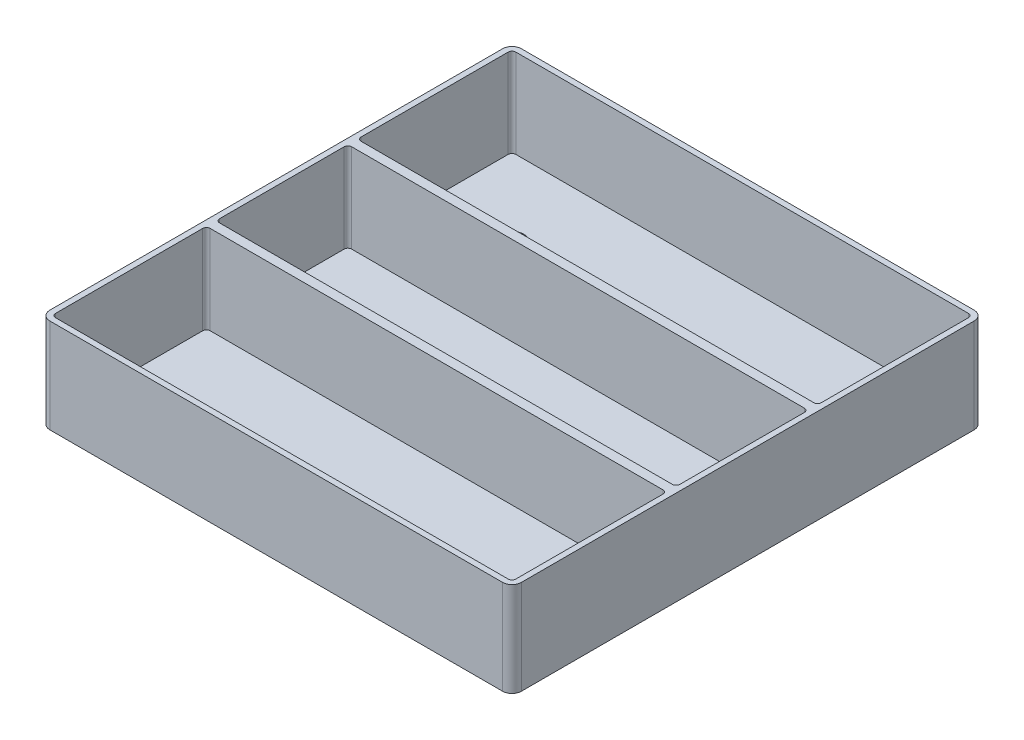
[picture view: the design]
ISO-10303-21;
HEADER;
FILE_DESCRIPTION(('STEP AP214'),'2;1');
FILE_NAME('part.step','',(''),(''),'','','');
FILE_SCHEMA(('AUTOMOTIVE_DESIGN { 1 0 10303 214 1 1 1 1 }'));
ENDSEC;
DATA;
#1=APPLICATION_CONTEXT('core data for automotive mechanical design processes');
#2=APPLICATION_PROTOCOL_DEFINITION('international standard','automotive_design',2000,#1);
#3=PRODUCT_CONTEXT('',#1,'mechanical');
#4=PRODUCT('Part','Part','',(#3));
#5=PRODUCT_RELATED_PRODUCT_CATEGORY('part','',(#4));
#6=PRODUCT_DEFINITION_FORMATION('','',#4);
#7=PRODUCT_DEFINITION_CONTEXT('part definition',#1,'design');
#8=PRODUCT_DEFINITION('design','',#6,#7);
#9=PRODUCT_DEFINITION_SHAPE('','',#8);
#10=(LENGTH_UNIT() NAMED_UNIT(*) SI_UNIT(.MILLI.,.METRE.));
#11=(NAMED_UNIT(*) PLANE_ANGLE_UNIT() SI_UNIT($,.RADIAN.));
#12=(NAMED_UNIT(*) SI_UNIT($,.STERADIAN.) SOLID_ANGLE_UNIT());
#13=UNCERTAINTY_MEASURE_WITH_UNIT(LENGTH_MEASURE(1.E-05),#10,'distance_accuracy_value','');
#14=(GEOMETRIC_REPRESENTATION_CONTEXT(3) GLOBAL_UNCERTAINTY_ASSIGNED_CONTEXT((#13)) GLOBAL_UNIT_ASSIGNED_CONTEXT((#10,
#11,#12)) REPRESENTATION_CONTEXT('',''));
#15=CARTESIAN_POINT('',(0.,0.,0.));
#16=DIRECTION('',(0.,0.,1.));
#17=DIRECTION('',(1.,0.,0.));
#18=AXIS2_PLACEMENT_3D('',#15,#16,#17);
#19=CARTESIAN_POINT('',(-61.976,25.4,-63.5));
#20=DIRECTION('',(1.,0.,0.));
#21=DIRECTION('',(0.,0.,-1.));
#22=AXIS2_PLACEMENT_3D('',#19,#20,#21);
#23=PLANE('',#22);
#24=DIRECTION('',(0.,0.,1.));
#25=VECTOR('',#24,1.);
#26=CARTESIAN_POINT('',(-61.976,1.524,-63.5));
#27=LINE('',#26,#25);
#28=CARTESIAN_POINT('',(-61.976,1.524,-16.764));
#29=VERTEX_POINT('',#28);
#30=CARTESIAN_POINT('',(-61.976,1.524,16.764));
#31=VERTEX_POINT('',#30);
#32=EDGE_CURVE('E515',#29,#31,#27,.T.);
#33=ORIENTED_EDGE('',*,*,#32,.F.);
#34=DIRECTION('',(0.,-1.,0.));
#35=VECTOR('',#34,1.);
#36=CARTESIAN_POINT('',(-61.976,25.4,-16.764));
#37=LINE('',#36,#35);
#38=CARTESIAN_POINT('',(-61.976,25.4,-16.764));
#39=VERTEX_POINT('',#38);
#40=EDGE_CURVE('E397',#29,#39,#37,.F.);
#41=ORIENTED_EDGE('',*,*,#40,.T.);
#42=DIRECTION('',(0.,0.,1.));
#43=VECTOR('',#42,1.);
#44=CARTESIAN_POINT('',(-61.976,25.4,-63.5));
#45=LINE('',#44,#43);
#46=CARTESIAN_POINT('',(-61.976,25.4,16.764));
#47=VERTEX_POINT('',#46);
#48=EDGE_CURVE('E288',#39,#47,#45,.T.);
#49=ORIENTED_EDGE('',*,*,#48,.T.);
#50=DIRECTION('',(0.,-1.,0.));
#51=VECTOR('',#50,1.);
#52=CARTESIAN_POINT('',(-61.976,25.4,16.764));
#53=LINE('',#52,#51);
#54=EDGE_CURVE('E394',#47,#31,#53,.T.);
#55=ORIENTED_EDGE('',*,*,#54,.T.);
#56=EDGE_LOOP('',(#33,#41,#49,#55));
#57=FACE_BOUND('',#56,.T.);
#58=ADVANCED_FACE('F41',(#57),#23,.T.);
#59=CARTESIAN_POINT('',(61.976,25.4,-63.5));
#60=DIRECTION('',(-1.,0.,0.));
#61=DIRECTION('',(0.,0.,1.));
#62=AXIS2_PLACEMENT_3D('',#59,#60,#61);
#63=PLANE('',#62);
#64=DIRECTION('',(0.,0.,-1.));
#65=VECTOR('',#64,1.);
#66=CARTESIAN_POINT('',(61.976,1.524,-63.5));
#67=LINE('',#66,#65);
#68=CARTESIAN_POINT('',(61.976,1.524,16.764));
#69=VERTEX_POINT('',#68);
#70=CARTESIAN_POINT('',(61.976,1.524,-16.764));
#71=VERTEX_POINT('',#70);
#72=EDGE_CURVE('E458',#69,#71,#67,.T.);
#73=ORIENTED_EDGE('',*,*,#72,.F.);
#74=DIRECTION('',(0.,-1.,0.));
#75=VECTOR('',#74,1.);
#76=CARTESIAN_POINT('',(61.976,25.4,16.764));
#77=LINE('',#76,#75);
#78=CARTESIAN_POINT('',(61.976,25.4,16.764));
#79=VERTEX_POINT('',#78);
#80=EDGE_CURVE('E421',#69,#79,#77,.F.);
#81=ORIENTED_EDGE('',*,*,#80,.T.);
#82=DIRECTION('',(0.,0.,-1.));
#83=VECTOR('',#82,1.);
#84=CARTESIAN_POINT('',(61.976,25.4,-63.5));
#85=LINE('',#84,#83);
#86=CARTESIAN_POINT('',(61.976,25.4,-16.764));
#87=VERTEX_POINT('',#86);
#88=EDGE_CURVE('E299',#79,#87,#85,.T.);
#89=ORIENTED_EDGE('',*,*,#88,.T.);
#90=DIRECTION('',(0.,-1.,0.));
#91=VECTOR('',#90,1.);
#92=CARTESIAN_POINT('',(61.976,25.4,-16.764));
#93=LINE('',#92,#91);
#94=EDGE_CURVE('E418',#87,#71,#93,.T.);
#95=ORIENTED_EDGE('',*,*,#94,.T.);
#96=EDGE_LOOP('',(#73,#81,#89,#95));
#97=FACE_BOUND('',#96,.T.);
#98=ADVANCED_FACE('F585',(#97),#63,.T.);
#99=CARTESIAN_POINT('',(-63.5,1.524,63.5));
#100=DIRECTION('',(0.,1.,0.));
#101=DIRECTION('',(0.,0.,1.));
#102=AXIS2_PLACEMENT_3D('',#99,#100,#101);
#103=PLANE('',#102);
#104=DIRECTION('',(-1.,0.,0.));
#105=VECTOR('',#104,1.);
#106=CARTESIAN_POINT('',(-63.5,1.524,-17.78));
#107=LINE('',#106,#105);
#108=CARTESIAN_POINT('',(60.96,1.524,-17.78));
#109=VERTEX_POINT('',#108);
#110=CARTESIAN_POINT('',(-60.96,1.524,-17.78));
#111=VERTEX_POINT('',#110);
#112=EDGE_CURVE('E362',#109,#111,#107,.T.);
#113=ORIENTED_EDGE('',*,*,#112,.T.);
#114=CARTESIAN_POINT('',(-60.96,1.524,-16.764));
#115=DIRECTION('',(0.,1.,0.));
#116=DIRECTION('',(0.,0.,1.));
#117=AXIS2_PLACEMENT_3D('',#114,#115,#116);
#118=CIRCLE('',#117,1.016);
#119=EDGE_CURVE('E392',#111,#29,#118,.T.);
#120=ORIENTED_EDGE('',*,*,#119,.T.);
#121=ORIENTED_EDGE('',*,*,#32,.T.);
#122=CARTESIAN_POINT('',(-60.96,1.524,16.764));
#123=DIRECTION('',(0.,1.,0.));
#124=DIRECTION('',(0.,0.,1.));
#125=AXIS2_PLACEMENT_3D('',#122,#123,#124);
#126=CIRCLE('',#125,1.016);
#127=CARTESIAN_POINT('',(-60.96,1.524,17.78));
#128=VERTEX_POINT('',#127);
#129=EDGE_CURVE('E390',#31,#128,#126,.T.);
#130=ORIENTED_EDGE('',*,*,#129,.T.);
#131=DIRECTION('',(1.,0.,0.));
#132=VECTOR('',#131,1.);
#133=CARTESIAN_POINT('',(-63.5,1.524,17.78));
#134=LINE('',#133,#132);
#135=CARTESIAN_POINT('',(60.96,1.524,17.78));
#136=VERTEX_POINT('',#135);
#137=EDGE_CURVE('E495',#128,#136,#134,.T.);
#138=ORIENTED_EDGE('',*,*,#137,.T.);
#139=CARTESIAN_POINT('',(60.96,1.524,16.764));
#140=DIRECTION('',(0.,1.,0.));
#141=DIRECTION('',(0.,0.,1.));
#142=AXIS2_PLACEMENT_3D('',#139,#140,#141);
#143=CIRCLE('',#142,1.016);
#144=EDGE_CURVE('E388',#136,#69,#143,.T.);
#145=ORIENTED_EDGE('',*,*,#144,.T.);
#146=ORIENTED_EDGE('',*,*,#72,.T.);
#147=CARTESIAN_POINT('',(60.96,1.524,-16.764));
#148=DIRECTION('',(0.,1.,0.));
#149=DIRECTION('',(0.,0.,1.));
#150=AXIS2_PLACEMENT_3D('',#147,#148,#149);
#151=CIRCLE('',#150,1.016);
#152=EDGE_CURVE('E386',#71,#109,#151,.T.);
#153=ORIENTED_EDGE('',*,*,#152,.T.);
#154=EDGE_LOOP('',(#113,#120,#121,#130,#138,#145,#146,#153));
#155=FACE_BOUND('',#154,.T.);
#156=ADVANCED_FACE('F593',(#155),#103,.T.);
#157=CARTESIAN_POINT('',(-61.976,1.524,21.336));
#158=VERTEX_POINT('',#157);
#159=CARTESIAN_POINT('',(-61.976,1.524,60.96));
#160=VERTEX_POINT('',#159);
#161=EDGE_CURVE('E449',#158,#160,#27,.T.);
#162=ORIENTED_EDGE('',*,*,#161,.F.);
#163=DIRECTION('',(0.,-1.,0.));
#164=VECTOR('',#163,1.);
#165=CARTESIAN_POINT('',(-61.976,25.4,21.336));
#166=LINE('',#165,#164);
#167=CARTESIAN_POINT('',(-61.976,25.4,21.336));
#168=VERTEX_POINT('',#167);
#169=EDGE_CURVE('E413',#158,#168,#166,.F.);
#170=ORIENTED_EDGE('',*,*,#169,.T.);
#171=CARTESIAN_POINT('',(-61.976,25.4,60.96));
#172=VERTEX_POINT('',#171);
#173=EDGE_CURVE('E271',#168,#172,#45,.T.);
#174=ORIENTED_EDGE('',*,*,#173,.T.);
#175=DIRECTION('',(0.,1.,0.));
#176=VECTOR('',#175,1.);
#177=CARTESIAN_POINT('',(-61.976,25.4,60.96));
#178=LINE('',#177,#176);
#179=EDGE_CURVE('E512',#160,#172,#178,.T.);
#180=ORIENTED_EDGE('',*,*,#179,.F.);
#181=EDGE_LOOP('',(#162,#170,#174,#180));
#182=FACE_BOUND('',#181,.T.);
#183=ADVANCED_FACE('F588',(#182),#23,.T.);
#184=CARTESIAN_POINT('',(61.976,25.4,60.96));
#185=VERTEX_POINT('',#184);
#186=CARTESIAN_POINT('',(61.976,25.4,21.336));
#187=VERTEX_POINT('',#186);
#188=EDGE_CURVE('E295',#185,#187,#85,.T.);
#189=ORIENTED_EDGE('',*,*,#188,.T.);
#190=DIRECTION('',(0.,-1.,0.));
#191=VECTOR('',#190,1.);
#192=CARTESIAN_POINT('',(61.976,1.524,21.336));
#193=LINE('',#192,#191);
#194=CARTESIAN_POINT('',(61.976,1.524,21.336));
#195=VERTEX_POINT('',#194);
#196=EDGE_CURVE('E415',#187,#195,#193,.T.);
#197=ORIENTED_EDGE('',*,*,#196,.T.);
#198=CARTESIAN_POINT('',(61.976,1.524,60.96));
#199=VERTEX_POINT('',#198);
#200=EDGE_CURVE('E272',#199,#195,#67,.T.);
#201=ORIENTED_EDGE('',*,*,#200,.F.);
#202=DIRECTION('',(0.,1.,0.));
#203=VECTOR('',#202,1.);
#204=CARTESIAN_POINT('',(61.976,25.4,60.96));
#205=LINE('',#204,#203);
#206=EDGE_CURVE('E478',#185,#199,#205,.F.);
#207=ORIENTED_EDGE('',*,*,#206,.F.);
#208=EDGE_LOOP('',(#189,#197,#201,#207));
#209=FACE_BOUND('',#208,.T.);
#210=ADVANCED_FACE('F477',(#209),#63,.T.);
#211=CARTESIAN_POINT('',(-41.275,1.524,41.275));
#212=DIRECTION('',(0.,1.,0.));
#213=DIRECTION('',(0.,0.,1.));
#214=AXIS2_PLACEMENT_3D('',#211,#212,#213);
#215=CIRCLE('',#214,3.175);
#216=CARTESIAN_POINT('',(-41.275,1.524,44.45));
#217=VERTEX_POINT('',#216);
#218=EDGE_CURVE('E1044',#217,#217,#215,.T.);
#219=ORIENTED_EDGE('',*,*,#218,.F.);
#220=EDGE_LOOP('',(#219));
#221=FACE_BOUND('',#220,.T.);
#222=CARTESIAN_POINT('',(44.45,1.524,41.275));
#223=DIRECTION('',(0.,1.,0.));
#224=DIRECTION('',(0.,0.,1.));
#225=AXIS2_PLACEMENT_3D('',#222,#223,#224);
#226=CIRCLE('',#225,3.175);
#227=CARTESIAN_POINT('',(44.45,1.524,44.45));
#228=VERTEX_POINT('',#227);
#229=EDGE_CURVE('E1047',#228,#228,#226,.T.);
#230=ORIENTED_EDGE('',*,*,#229,.F.);
#231=EDGE_LOOP('',(#230));
#232=FACE_BOUND('',#231,.T.);
#233=DIRECTION('',(1.,0.,0.));
#234=VECTOR('',#233,1.);
#235=CARTESIAN_POINT('',(-63.5,1.524,20.32));
#236=LINE('',#235,#234);
#237=CARTESIAN_POINT('',(-60.96,1.524,20.32));
#238=VERTEX_POINT('',#237);
#239=CARTESIAN_POINT('',(60.96,1.524,20.32));
#240=VERTEX_POINT('',#239);
#241=EDGE_CURVE('E491',#238,#240,#236,.T.);
#242=ORIENTED_EDGE('',*,*,#241,.F.);
#243=CARTESIAN_POINT('',(-60.96,1.524,21.336));
#244=DIRECTION('',(0.,1.,0.));
#245=DIRECTION('',(0.,0.,1.));
#246=AXIS2_PLACEMENT_3D('',#243,#244,#245);
#247=CIRCLE('',#246,1.016);
#248=EDGE_CURVE('E411',#238,#158,#247,.T.);
#249=ORIENTED_EDGE('',*,*,#248,.T.);
#250=ORIENTED_EDGE('',*,*,#161,.T.);
#251=CARTESIAN_POINT('',(-60.96,1.524,60.96));
#252=DIRECTION('',(0.,1.,0.));
#253=DIRECTION('',(0.,0.,1.));
#254=AXIS2_PLACEMENT_3D('',#251,#252,#253);
#255=CIRCLE('',#254,1.016);
#256=CARTESIAN_POINT('',(-60.96,1.524,61.976));
#257=VERTEX_POINT('',#256);
#258=EDGE_CURVE('E511',#257,#160,#255,.F.);
#259=ORIENTED_EDGE('',*,*,#258,.F.);
#260=DIRECTION('',(1.,0.,0.));
#261=VECTOR('',#260,1.);
#262=CARTESIAN_POINT('',(-63.5,1.524,61.976));
#263=LINE('',#262,#261);
#264=CARTESIAN_POINT('',(60.96,1.524,61.976));
#265=VERTEX_POINT('',#264);
#266=EDGE_CURVE('E459',#257,#265,#263,.T.);
#267=ORIENTED_EDGE('',*,*,#266,.T.);
#268=CARTESIAN_POINT('',(60.96,1.524,60.96));
#269=DIRECTION('',(0.,1.,0.));
#270=DIRECTION('',(0.,0.,1.));
#271=AXIS2_PLACEMENT_3D('',#268,#269,#270);
#272=CIRCLE('',#271,1.016);
#273=EDGE_CURVE('E473',#199,#265,#272,.F.);
#274=ORIENTED_EDGE('',*,*,#273,.F.);
#275=ORIENTED_EDGE('',*,*,#200,.T.);
#276=CARTESIAN_POINT('',(60.96,1.524,21.336));
#277=DIRECTION('',(0.,1.,0.));
#278=DIRECTION('',(0.,0.,1.));
#279=AXIS2_PLACEMENT_3D('',#276,#277,#278);
#280=CIRCLE('',#279,1.016);
#281=EDGE_CURVE('E409',#195,#240,#280,.T.);
#282=ORIENTED_EDGE('',*,*,#281,.T.);
#283=EDGE_LOOP('',(#242,#249,#250,#259,#267,#274,#275,#282));
#284=FACE_BOUND('',#283,.T.);
#285=ADVANCED_FACE('F471',(#221,#232,#284),#103,.T.);
#286=CARTESIAN_POINT('',(-63.5,25.4,-63.5));
#287=DIRECTION('',(1.,0.,0.));
#288=DIRECTION('',(0.,0.,-1.));
#289=AXIS2_PLACEMENT_3D('',#286,#287,#288);
#290=PLANE('',#289);
#291=DIRECTION('',(0.,-1.,0.));
#292=VECTOR('',#291,1.);
#293=CARTESIAN_POINT('',(-63.5,25.4,60.96));
#294=LINE('',#293,#292);
#295=CARTESIAN_POINT('',(-63.5,0.,60.96));
#296=VERTEX_POINT('',#295);
#297=CARTESIAN_POINT('',(-63.5,25.4,60.96));
#298=VERTEX_POINT('',#297);
#299=EDGE_CURVE('E322',#296,#298,#294,.F.);
#300=ORIENTED_EDGE('',*,*,#299,.T.);
#301=DIRECTION('',(0.,0.,1.));
#302=VECTOR('',#301,1.);
#303=CARTESIAN_POINT('',(-63.5,25.4,-63.5));
#304=LINE('',#303,#302);
#305=CARTESIAN_POINT('',(-63.5,25.4,-60.96));
#306=VERTEX_POINT('',#305);
#307=EDGE_CURVE('E321',#306,#298,#304,.T.);
#308=ORIENTED_EDGE('',*,*,#307,.F.);
#309=DIRECTION('',(0.,-1.,0.));
#310=VECTOR('',#309,1.);
#311=CARTESIAN_POINT('',(-63.5,25.4,-60.96));
#312=LINE('',#311,#310);
#313=CARTESIAN_POINT('',(-63.5,0.,-60.96));
#314=VERTEX_POINT('',#313);
#315=EDGE_CURVE('E325',#306,#314,#312,.T.);
#316=ORIENTED_EDGE('',*,*,#315,.T.);
#317=DIRECTION('',(0.,0.,1.));
#318=VECTOR('',#317,1.);
#319=CARTESIAN_POINT('',(-63.5,0.,-63.5));
#320=LINE('',#319,#318);
#321=EDGE_CURVE('E303',#314,#296,#320,.T.);
#322=ORIENTED_EDGE('',*,*,#321,.T.);
#323=EDGE_LOOP('',(#300,#308,#316,#322));
#324=FACE_BOUND('',#323,.T.);
#325=ADVANCED_FACE('F550',(#324),#290,.F.);
#326=CARTESIAN_POINT('',(-63.5,25.4,63.5));
#327=DIRECTION('',(0.,0.,-1.));
#328=DIRECTION('',(-1.,0.,0.));
#329=AXIS2_PLACEMENT_3D('',#326,#327,#328);
#330=PLANE('',#329);
#331=DIRECTION('',(1.,0.,0.));
#332=VECTOR('',#331,1.);
#333=CARTESIAN_POINT('',(-63.5,0.,63.5));
#334=LINE('',#333,#332);
#335=CARTESIAN_POINT('',(-60.96,0.,63.5));
#336=VERTEX_POINT('',#335);
#337=CARTESIAN_POINT('',(60.96,0.,63.5));
#338=VERTEX_POINT('',#337);
#339=EDGE_CURVE('E308',#336,#338,#334,.T.);
#340=ORIENTED_EDGE('',*,*,#339,.T.);
#341=DIRECTION('',(0.,-1.,0.));
#342=VECTOR('',#341,1.);
#343=CARTESIAN_POINT('',(60.96,25.4,63.5));
#344=LINE('',#343,#342);
#345=CARTESIAN_POINT('',(60.96,25.4,63.5));
#346=VERTEX_POINT('',#345);
#347=EDGE_CURVE('E360',#338,#346,#344,.F.);
#348=ORIENTED_EDGE('',*,*,#347,.T.);
#349=DIRECTION('',(1.,0.,0.));
#350=VECTOR('',#349,1.);
#351=CARTESIAN_POINT('',(-63.5,25.4,63.5));
#352=LINE('',#351,#350);
#353=CARTESIAN_POINT('',(-60.96,25.4,63.5));
#354=VERTEX_POINT('',#353);
#355=EDGE_CURVE('E530',#354,#346,#352,.T.);
#356=ORIENTED_EDGE('',*,*,#355,.F.);
#357=DIRECTION('',(0.,-1.,0.));
#358=VECTOR('',#357,1.);
#359=CARTESIAN_POINT('',(-60.96,25.4,63.5));
#360=LINE('',#359,#358);
#361=EDGE_CURVE('E357',#354,#336,#360,.T.);
#362=ORIENTED_EDGE('',*,*,#361,.T.);
#363=EDGE_LOOP('',(#340,#348,#356,#362));
#364=FACE_BOUND('',#363,.T.);
#365=ADVANCED_FACE('F563',(#364),#330,.F.);
#366=CARTESIAN_POINT('',(63.5,25.4,-63.5));
#367=DIRECTION('',(-1.,0.,0.));
#368=DIRECTION('',(0.,0.,1.));
#369=AXIS2_PLACEMENT_3D('',#366,#367,#368);
#370=PLANE('',#369);
#371=DIRECTION('',(0.,-1.,0.));
#372=VECTOR('',#371,1.);
#373=CARTESIAN_POINT('',(63.5,25.4,-60.96));
#374=LINE('',#373,#372);
#375=CARTESIAN_POINT('',(63.5,0.,-60.96));
#376=VERTEX_POINT('',#375);
#377=CARTESIAN_POINT('',(63.5,25.4,-60.96));
#378=VERTEX_POINT('',#377);
#379=EDGE_CURVE('E354',#376,#378,#374,.F.);
#380=ORIENTED_EDGE('',*,*,#379,.T.);
#381=DIRECTION('',(0.,0.,-1.));
#382=VECTOR('',#381,1.);
#383=CARTESIAN_POINT('',(63.5,25.4,-63.5));
#384=LINE('',#383,#382);
#385=CARTESIAN_POINT('',(63.5,25.4,60.96));
#386=VERTEX_POINT('',#385);
#387=EDGE_CURVE('E534',#386,#378,#384,.T.);
#388=ORIENTED_EDGE('',*,*,#387,.F.);
#389=DIRECTION('',(0.,-1.,0.));
#390=VECTOR('',#389,1.);
#391=CARTESIAN_POINT('',(63.5,25.4,60.96));
#392=LINE('',#391,#390);
#393=CARTESIAN_POINT('',(63.5,0.,60.96));
#394=VERTEX_POINT('',#393);
#395=EDGE_CURVE('E351',#386,#394,#392,.T.);
#396=ORIENTED_EDGE('',*,*,#395,.T.);
#397=DIRECTION('',(0.,0.,-1.));
#398=VECTOR('',#397,1.);
#399=CARTESIAN_POINT('',(63.5,0.,-63.5));
#400=LINE('',#399,#398);
#401=EDGE_CURVE('E314',#394,#376,#400,.T.);
#402=ORIENTED_EDGE('',*,*,#401,.T.);
#403=EDGE_LOOP('',(#380,#388,#396,#402));
#404=FACE_BOUND('',#403,.T.);
#405=ADVANCED_FACE('F569',(#404),#370,.F.);
#406=CARTESIAN_POINT('',(-63.5,25.4,-63.5));
#407=DIRECTION('',(0.,0.,1.));
#408=DIRECTION('',(1.,0.,0.));
#409=AXIS2_PLACEMENT_3D('',#406,#407,#408);
#410=PLANE('',#409);
#411=DIRECTION('',(-1.,0.,0.));
#412=VECTOR('',#411,1.);
#413=CARTESIAN_POINT('',(-63.5,0.,-63.5));
#414=LINE('',#413,#412);
#415=CARTESIAN_POINT('',(60.96,0.,-63.5));
#416=VERTEX_POINT('',#415);
#417=CARTESIAN_POINT('',(-60.96,0.,-63.5));
#418=VERTEX_POINT('',#417);
#419=EDGE_CURVE('E317',#416,#418,#414,.T.);
#420=ORIENTED_EDGE('',*,*,#419,.T.);
#421=DIRECTION('',(0.,-1.,0.));
#422=VECTOR('',#421,1.);
#423=CARTESIAN_POINT('',(-60.96,25.4,-63.5));
#424=LINE('',#423,#422);
#425=CARTESIAN_POINT('',(-60.96,25.4,-63.5));
#426=VERTEX_POINT('',#425);
#427=EDGE_CURVE('E341',#418,#426,#424,.F.);
#428=ORIENTED_EDGE('',*,*,#427,.T.);
#429=DIRECTION('',(-1.,0.,0.));
#430=VECTOR('',#429,1.);
#431=CARTESIAN_POINT('',(-63.5,25.4,-63.5));
#432=LINE('',#431,#430);
#433=CARTESIAN_POINT('',(60.96,25.4,-63.5));
#434=VERTEX_POINT('',#433);
#435=EDGE_CURVE('E310',#434,#426,#432,.T.);
#436=ORIENTED_EDGE('',*,*,#435,.F.);
#437=DIRECTION('',(0.,-1.,0.));
#438=VECTOR('',#437,1.);
#439=CARTESIAN_POINT('',(60.96,25.4,-63.5));
#440=LINE('',#439,#438);
#441=EDGE_CURVE('E338',#434,#416,#440,.T.);
#442=ORIENTED_EDGE('',*,*,#441,.T.);
#443=EDGE_LOOP('',(#420,#428,#436,#442));
#444=FACE_BOUND('',#443,.T.);
#445=ADVANCED_FACE('F574',(#444),#410,.F.);
#446=CARTESIAN_POINT('',(-63.5,25.4,63.5));
#447=DIRECTION('',(0.,1.,0.));
#448=DIRECTION('',(0.,0.,1.));
#449=AXIS2_PLACEMENT_3D('',#446,#447,#448);
#450=PLANE('',#449);
#451=ORIENTED_EDGE('',*,*,#173,.F.);
#452=CARTESIAN_POINT('',(-60.96,25.4,21.336));
#453=DIRECTION('',(0.,1.,0.));
#454=DIRECTION('',(0.,0.,1.));
#455=AXIS2_PLACEMENT_3D('',#452,#453,#454);
#456=CIRCLE('',#455,1.016);
#457=CARTESIAN_POINT('',(-60.96,25.4,20.32));
#458=VERTEX_POINT('',#457);
#459=EDGE_CURVE('E430',#168,#458,#456,.F.);
#460=ORIENTED_EDGE('',*,*,#459,.T.);
#461=DIRECTION('',(1.,0.,0.));
#462=VECTOR('',#461,1.);
#463=CARTESIAN_POINT('',(61.976,25.4,20.32));
#464=LINE('',#463,#462);
#465=CARTESIAN_POINT('',(60.96,25.4,20.32));
#466=VERTEX_POINT('',#465);
#467=EDGE_CURVE('E489',#466,#458,#464,.F.);
#468=ORIENTED_EDGE('',*,*,#467,.F.);
#469=CARTESIAN_POINT('',(60.96,25.4,21.336));
#470=DIRECTION('',(0.,1.,0.));
#471=DIRECTION('',(0.,0.,1.));
#472=AXIS2_PLACEMENT_3D('',#469,#470,#471);
#473=CIRCLE('',#472,1.016);
#474=EDGE_CURVE('E432',#466,#187,#473,.F.);
#475=ORIENTED_EDGE('',*,*,#474,.T.);
#476=ORIENTED_EDGE('',*,*,#188,.F.);
#477=CARTESIAN_POINT('',(60.96,25.4,60.96));
#478=DIRECTION('',(0.,1.,0.));
#479=DIRECTION('',(0.,0.,1.));
#480=AXIS2_PLACEMENT_3D('',#477,#478,#479);
#481=CIRCLE('',#480,1.016);
#482=CARTESIAN_POINT('',(60.96,25.4,61.976));
#483=VERTEX_POINT('',#482);
#484=EDGE_CURVE('E280',#483,#185,#481,.T.);
#485=ORIENTED_EDGE('',*,*,#484,.F.);
#486=DIRECTION('',(1.,0.,0.));
#487=VECTOR('',#486,1.);
#488=CARTESIAN_POINT('',(-63.5,25.4,61.976));
#489=LINE('',#488,#487);
#490=CARTESIAN_POINT('',(-60.96,25.4,61.976));
#491=VERTEX_POINT('',#490);
#492=EDGE_CURVE('E287',#491,#483,#489,.T.);
#493=ORIENTED_EDGE('',*,*,#492,.F.);
#494=CARTESIAN_POINT('',(-60.96,25.4,60.96));
#495=DIRECTION('',(0.,1.,0.));
#496=DIRECTION('',(0.,0.,1.));
#497=AXIS2_PLACEMENT_3D('',#494,#495,#496);
#498=CIRCLE('',#497,1.016);
#499=EDGE_CURVE('E278',#172,#491,#498,.T.);
#500=ORIENTED_EDGE('',*,*,#499,.F.);
#501=EDGE_LOOP('',(#451,#460,#468,#475,#476,#485,#493,#500));
#502=FACE_BOUND('',#501,.T.);
#503=ORIENTED_EDGE('',*,*,#88,.F.);
#504=CARTESIAN_POINT('',(60.96,25.4,16.764));
#505=DIRECTION('',(0.,1.,0.));
#506=DIRECTION('',(0.,0.,1.));
#507=AXIS2_PLACEMENT_3D('',#504,#505,#506);
#508=CIRCLE('',#507,1.016);
#509=CARTESIAN_POINT('',(60.96,25.4,17.78));
#510=VERTEX_POINT('',#509);
#511=EDGE_CURVE('E434',#79,#510,#508,.F.);
#512=ORIENTED_EDGE('',*,*,#511,.T.);
#513=DIRECTION('',(1.,0.,0.));
#514=VECTOR('',#513,1.);
#515=CARTESIAN_POINT('',(61.976,25.4,17.78));
#516=LINE('',#515,#514);
#517=CARTESIAN_POINT('',(-60.96,25.4,17.78));
#518=VERTEX_POINT('',#517);
#519=EDGE_CURVE('E496',#510,#518,#516,.F.);
#520=ORIENTED_EDGE('',*,*,#519,.T.);
#521=CARTESIAN_POINT('',(-60.96,25.4,16.764));
#522=DIRECTION('',(0.,1.,0.));
#523=DIRECTION('',(0.,0.,1.));
#524=AXIS2_PLACEMENT_3D('',#521,#522,#523);
#525=CIRCLE('',#524,1.016);
#526=EDGE_CURVE('E428',#518,#47,#525,.F.);
#527=ORIENTED_EDGE('',*,*,#526,.T.);
#528=ORIENTED_EDGE('',*,*,#48,.F.);
#529=CARTESIAN_POINT('',(-60.96,25.4,-16.764));
#530=DIRECTION('',(0.,1.,0.));
#531=DIRECTION('',(0.,0.,1.));
#532=AXIS2_PLACEMENT_3D('',#529,#530,#531);
#533=CIRCLE('',#532,1.016);
#534=CARTESIAN_POINT('',(-60.96,25.4,-17.78));
#535=VERTEX_POINT('',#534);
#536=EDGE_CURVE('E426',#39,#535,#533,.F.);
#537=ORIENTED_EDGE('',*,*,#536,.T.);
#538=DIRECTION('',(-1.,0.,0.));
#539=VECTOR('',#538,1.);
#540=CARTESIAN_POINT('',(-61.976,25.4,-17.78));
#541=LINE('',#540,#539);
#542=CARTESIAN_POINT('',(60.96,25.4,-17.78));
#543=VERTEX_POINT('',#542);
#544=EDGE_CURVE('E450',#535,#543,#541,.F.);
#545=ORIENTED_EDGE('',*,*,#544,.T.);
#546=CARTESIAN_POINT('',(60.96,25.4,-16.764));
#547=DIRECTION('',(0.,1.,0.));
#548=DIRECTION('',(0.,0.,1.));
#549=AXIS2_PLACEMENT_3D('',#546,#547,#548);
#550=CIRCLE('',#549,1.016);
#551=EDGE_CURVE('E12',#543,#87,#550,.F.);
#552=ORIENTED_EDGE('',*,*,#551,.T.);
#553=EDGE_LOOP('',(#503,#512,#520,#527,#528,#537,#545,#552));
#554=FACE_BOUND('',#553,.T.);
#555=ORIENTED_EDGE('',*,*,#387,.T.);
#556=CARTESIAN_POINT('',(60.96,25.4,-60.96));
#557=DIRECTION('',(0.,1.,0.));
#558=DIRECTION('',(0.,0.,1.));
#559=AXIS2_PLACEMENT_3D('',#556,#557,#558);
#560=CIRCLE('',#559,2.54);
#561=EDGE_CURVE('E347',#378,#434,#560,.T.);
#562=ORIENTED_EDGE('',*,*,#561,.T.);
#563=ORIENTED_EDGE('',*,*,#435,.T.);
#564=CARTESIAN_POINT('',(-60.96,25.4,-60.96));
#565=DIRECTION('',(0.,1.,0.));
#566=DIRECTION('',(0.,0.,1.));
#567=AXIS2_PLACEMENT_3D('',#564,#565,#566);
#568=CIRCLE('',#567,2.54);
#569=EDGE_CURVE('E349',#426,#306,#568,.T.);
#570=ORIENTED_EDGE('',*,*,#569,.T.);
#571=ORIENTED_EDGE('',*,*,#307,.T.);
#572=CARTESIAN_POINT('',(-60.96,25.4,60.96));
#573=DIRECTION('',(0.,1.,0.));
#574=DIRECTION('',(0.,0.,1.));
#575=AXIS2_PLACEMENT_3D('',#572,#573,#574);
#576=CIRCLE('',#575,2.54);
#577=EDGE_CURVE('E343',#298,#354,#576,.T.);
#578=ORIENTED_EDGE('',*,*,#577,.T.);
#579=ORIENTED_EDGE('',*,*,#355,.T.);
#580=CARTESIAN_POINT('',(60.96,25.4,60.96));
#581=DIRECTION('',(0.,1.,0.));
#582=DIRECTION('',(0.,0.,1.));
#583=AXIS2_PLACEMENT_3D('',#580,#581,#582);
#584=CIRCLE('',#583,2.54);
#585=EDGE_CURVE('E345',#346,#386,#584,.T.);
#586=ORIENTED_EDGE('',*,*,#585,.T.);
#587=EDGE_LOOP('',(#555,#562,#563,#570,#571,#578,#579,#586));
#588=FACE_BOUND('',#587,.T.);
#589=DIRECTION('',(-1.,0.,0.));
#590=VECTOR('',#589,1.);
#591=CARTESIAN_POINT('',(-61.976,25.4,-20.32));
#592=LINE('',#591,#590);
#593=CARTESIAN_POINT('',(-60.96,25.4,-20.32));
#594=VERTEX_POINT('',#593);
#595=CARTESIAN_POINT('',(60.96,25.4,-20.32));
#596=VERTEX_POINT('',#595);
#597=EDGE_CURVE('E440',#594,#596,#592,.F.);
#598=ORIENTED_EDGE('',*,*,#597,.F.);
#599=CARTESIAN_POINT('',(-60.96,25.4,-21.336));
#600=DIRECTION('',(0.,1.,0.));
#601=DIRECTION('',(0.,0.,1.));
#602=AXIS2_PLACEMENT_3D('',#599,#600,#601);
#603=CIRCLE('',#602,1.016);
#604=CARTESIAN_POINT('',(-61.976,25.4,-21.336));
#605=VERTEX_POINT('',#604);
#606=EDGE_CURVE('E424',#594,#605,#603,.F.);
#607=ORIENTED_EDGE('',*,*,#606,.T.);
#608=CARTESIAN_POINT('',(-61.976,25.4,-60.96));
#609=VERTEX_POINT('',#608);
#610=EDGE_CURVE('E285',#609,#605,#45,.T.);
#611=ORIENTED_EDGE('',*,*,#610,.F.);
#612=CARTESIAN_POINT('',(-60.96,25.4,-60.96));
#613=DIRECTION('',(0.,1.,0.));
#614=DIRECTION('',(0.,0.,1.));
#615=AXIS2_PLACEMENT_3D('',#612,#613,#614);
#616=CIRCLE('',#615,1.016);
#617=CARTESIAN_POINT('',(-60.96,25.4,-61.976));
#618=VERTEX_POINT('',#617);
#619=EDGE_CURVE('E526',#618,#609,#616,.T.);
#620=ORIENTED_EDGE('',*,*,#619,.F.);
#621=DIRECTION('',(-1.,0.,0.));
#622=VECTOR('',#621,1.);
#623=CARTESIAN_POINT('',(-63.5,25.4,-61.976));
#624=LINE('',#623,#622);
#625=CARTESIAN_POINT('',(60.96,25.4,-61.976));
#626=VERTEX_POINT('',#625);
#627=EDGE_CURVE('E276',#626,#618,#624,.T.);
#628=ORIENTED_EDGE('',*,*,#627,.F.);
#629=CARTESIAN_POINT('',(60.96,25.4,-60.96));
#630=DIRECTION('',(0.,1.,0.));
#631=DIRECTION('',(0.,0.,1.));
#632=AXIS2_PLACEMENT_3D('',#629,#630,#631);
#633=CIRCLE('',#632,1.016);
#634=CARTESIAN_POINT('',(61.976,25.4,-60.96));
#635=VERTEX_POINT('',#634);
#636=EDGE_CURVE('E294',#635,#626,#633,.T.);
#637=ORIENTED_EDGE('',*,*,#636,.F.);
#638=CARTESIAN_POINT('',(61.976,25.4,-21.336));
#639=VERTEX_POINT('',#638);
#640=EDGE_CURVE('E292',#639,#635,#85,.T.);
#641=ORIENTED_EDGE('',*,*,#640,.F.);
#642=CARTESIAN_POINT('',(60.96,25.4,-21.336));
#643=DIRECTION('',(0.,1.,0.));
#644=DIRECTION('',(0.,0.,1.));
#645=AXIS2_PLACEMENT_3D('',#642,#643,#644);
#646=CIRCLE('',#645,1.016);
#647=EDGE_CURVE('E49',#639,#596,#646,.F.);
#648=ORIENTED_EDGE('',*,*,#647,.T.);
#649=EDGE_LOOP('',(#598,#607,#611,#620,#628,#637,#641,#648));
#650=FACE_BOUND('',#649,.T.);
#651=ADVANCED_FACE('F439',(#502,#554,#588,#650),#450,.T.);
#652=CARTESIAN_POINT('',(-63.5,0.,63.5));
#653=DIRECTION('',(0.,1.,0.));
#654=DIRECTION('',(0.,0.,1.));
#655=AXIS2_PLACEMENT_3D('',#652,#653,#654);
#656=PLANE('',#655);
#657=CARTESIAN_POINT('',(-41.275,0.,41.275));
#658=DIRECTION('',(0.,1.,0.));
#659=DIRECTION('',(0.,0.,1.));
#660=AXIS2_PLACEMENT_3D('',#657,#658,#659);
#661=CIRCLE('',#660,3.175);
#662=CARTESIAN_POINT('',(-41.275,0.,44.45));
#663=VERTEX_POINT('',#662);
#664=EDGE_CURVE('E1050',#663,#663,#661,.T.);
#665=ORIENTED_EDGE('',*,*,#664,.T.);
#666=EDGE_LOOP('',(#665));
#667=FACE_BOUND('',#666,.T.);
#668=CARTESIAN_POINT('',(44.45,0.,41.275));
#669=DIRECTION('',(0.,1.,0.));
#670=DIRECTION('',(0.,0.,1.));
#671=AXIS2_PLACEMENT_3D('',#668,#669,#670);
#672=CIRCLE('',#671,3.175);
#673=CARTESIAN_POINT('',(44.45,0.,44.45));
#674=VERTEX_POINT('',#673);
#675=EDGE_CURVE('E1049',#674,#674,#672,.T.);
#676=ORIENTED_EDGE('',*,*,#675,.T.);
#677=EDGE_LOOP('',(#676));
#678=FACE_BOUND('',#677,.T.);
#679=CARTESIAN_POINT('',(-41.275,0.,-41.275));
#680=DIRECTION('',(0.,1.,0.));
#681=DIRECTION('',(0.,0.,1.));
#682=AXIS2_PLACEMENT_3D('',#679,#680,#681);
#683=CIRCLE('',#682,3.175);
#684=CARTESIAN_POINT('',(-41.275,0.,-38.1));
#685=VERTEX_POINT('',#684);
#686=EDGE_CURVE('E1059',#685,#685,#683,.T.);
#687=ORIENTED_EDGE('',*,*,#686,.T.);
#688=EDGE_LOOP('',(#687));
#689=FACE_BOUND('',#688,.T.);
#690=CARTESIAN_POINT('',(44.45,0.,-41.275));
#691=DIRECTION('',(0.,1.,0.));
#692=DIRECTION('',(0.,0.,1.));
#693=AXIS2_PLACEMENT_3D('',#690,#691,#692);
#694=CIRCLE('',#693,3.175);
#695=CARTESIAN_POINT('',(44.45,0.,-38.1));
#696=VERTEX_POINT('',#695);
#697=EDGE_CURVE('E501',#696,#696,#694,.T.);
#698=ORIENTED_EDGE('',*,*,#697,.T.);
#699=EDGE_LOOP('',(#698));
#700=FACE_BOUND('',#699,.T.);
#701=CARTESIAN_POINT('',(60.96,0.,-60.96));
#702=DIRECTION('',(0.,1.,0.));
#703=DIRECTION('',(0.,0.,1.));
#704=AXIS2_PLACEMENT_3D('',#701,#702,#703);
#705=CIRCLE('',#704,2.54);
#706=EDGE_CURVE('E333',#416,#376,#705,.F.);
#707=ORIENTED_EDGE('',*,*,#706,.T.);
#708=ORIENTED_EDGE('',*,*,#401,.F.);
#709=CARTESIAN_POINT('',(60.96,0.,60.96));
#710=DIRECTION('',(0.,1.,0.));
#711=DIRECTION('',(0.,0.,1.));
#712=AXIS2_PLACEMENT_3D('',#709,#710,#711);
#713=CIRCLE('',#712,2.54);
#714=EDGE_CURVE('E331',#394,#338,#713,.F.);
#715=ORIENTED_EDGE('',*,*,#714,.T.);
#716=ORIENTED_EDGE('',*,*,#339,.F.);
#717=CARTESIAN_POINT('',(-60.96,0.,60.96));
#718=DIRECTION('',(0.,1.,0.));
#719=DIRECTION('',(0.,0.,1.));
#720=AXIS2_PLACEMENT_3D('',#717,#718,#719);
#721=CIRCLE('',#720,2.54);
#722=EDGE_CURVE('E328',#336,#296,#721,.F.);
#723=ORIENTED_EDGE('',*,*,#722,.T.);
#724=ORIENTED_EDGE('',*,*,#321,.F.);
#725=CARTESIAN_POINT('',(-60.96,0.,-60.96));
#726=DIRECTION('',(0.,1.,0.));
#727=DIRECTION('',(0.,0.,1.));
#728=AXIS2_PLACEMENT_3D('',#725,#726,#727);
#729=CIRCLE('',#728,2.54);
#730=EDGE_CURVE('E336',#314,#418,#729,.F.);
#731=ORIENTED_EDGE('',*,*,#730,.T.);
#732=ORIENTED_EDGE('',*,*,#419,.F.);
#733=EDGE_LOOP('',(#707,#708,#715,#716,#723,#724,#731,#732));
#734=FACE_BOUND('',#733,.T.);
#735=ADVANCED_FACE('F552',(#667,#678,#689,#700,#734),#656,.F.);
#736=CARTESIAN_POINT('',(-60.96,25.4,-60.96));
#737=DIRECTION('',(0.,-1.,0.));
#738=DIRECTION('',(0.,0.,-1.));
#739=AXIS2_PLACEMENT_3D('',#736,#737,#738);
#740=CYLINDRICAL_SURFACE('',#739,2.54);
#741=ORIENTED_EDGE('',*,*,#569,.F.);
#742=ORIENTED_EDGE('',*,*,#427,.F.);
#743=ORIENTED_EDGE('',*,*,#730,.F.);
#744=ORIENTED_EDGE('',*,*,#315,.F.);
#745=EDGE_LOOP('',(#741,#742,#743,#744));
#746=FACE_BOUND('',#745,.T.);
#747=ADVANCED_FACE('F547',(#746),#740,.T.);
#748=CARTESIAN_POINT('',(60.96,25.4,-60.96));
#749=DIRECTION('',(0.,-1.,0.));
#750=DIRECTION('',(0.,0.,-1.));
#751=AXIS2_PLACEMENT_3D('',#748,#749,#750);
#752=CYLINDRICAL_SURFACE('',#751,2.54);
#753=ORIENTED_EDGE('',*,*,#561,.F.);
#754=ORIENTED_EDGE('',*,*,#379,.F.);
#755=ORIENTED_EDGE('',*,*,#706,.F.);
#756=ORIENTED_EDGE('',*,*,#441,.F.);
#757=EDGE_LOOP('',(#753,#754,#755,#756));
#758=FACE_BOUND('',#757,.T.);
#759=ADVANCED_FACE('F573',(#758),#752,.T.);
#760=CARTESIAN_POINT('',(60.96,25.4,60.96));
#761=DIRECTION('',(0.,-1.,0.));
#762=DIRECTION('',(0.,0.,-1.));
#763=AXIS2_PLACEMENT_3D('',#760,#761,#762);
#764=CYLINDRICAL_SURFACE('',#763,2.54);
#765=ORIENTED_EDGE('',*,*,#585,.F.);
#766=ORIENTED_EDGE('',*,*,#347,.F.);
#767=ORIENTED_EDGE('',*,*,#714,.F.);
#768=ORIENTED_EDGE('',*,*,#395,.F.);
#769=EDGE_LOOP('',(#765,#766,#767,#768));
#770=FACE_BOUND('',#769,.T.);
#771=ADVANCED_FACE('F566',(#770),#764,.T.);
#772=CARTESIAN_POINT('',(-60.96,25.4,60.96));
#773=DIRECTION('',(0.,-1.,0.));
#774=DIRECTION('',(0.,0.,-1.));
#775=AXIS2_PLACEMENT_3D('',#772,#773,#774);
#776=CYLINDRICAL_SURFACE('',#775,2.54);
#777=ORIENTED_EDGE('',*,*,#577,.F.);
#778=ORIENTED_EDGE('',*,*,#299,.F.);
#779=ORIENTED_EDGE('',*,*,#722,.F.);
#780=ORIENTED_EDGE('',*,*,#361,.F.);
#781=EDGE_LOOP('',(#777,#778,#779,#780));
#782=FACE_BOUND('',#781,.T.);
#783=ADVANCED_FACE('F559',(#782),#776,.T.);
#784=ORIENTED_EDGE('',*,*,#610,.T.);
#785=DIRECTION('',(0.,-1.,0.));
#786=VECTOR('',#785,1.);
#787=CARTESIAN_POINT('',(-61.976,1.524,-21.336));
#788=LINE('',#787,#786);
#789=CARTESIAN_POINT('',(-61.976,1.524,-21.336));
#790=VERTEX_POINT('',#789);
#791=EDGE_CURVE('E366',#605,#790,#788,.T.);
#792=ORIENTED_EDGE('',*,*,#791,.T.);
#793=CARTESIAN_POINT('',(-61.976,1.524,-60.96));
#794=VERTEX_POINT('',#793);
#795=EDGE_CURVE('E463',#794,#790,#27,.T.);
#796=ORIENTED_EDGE('',*,*,#795,.F.);
#797=DIRECTION('',(0.,1.,0.));
#798=VECTOR('',#797,1.);
#799=CARTESIAN_POINT('',(-61.976,25.4,-60.96));
#800=LINE('',#799,#798);
#801=EDGE_CURVE('E257',#609,#794,#800,.F.);
#802=ORIENTED_EDGE('',*,*,#801,.F.);
#803=EDGE_LOOP('',(#784,#792,#796,#802));
#804=FACE_BOUND('',#803,.T.);
#805=ADVANCED_FACE('F589',(#804),#23,.T.);
#806=CARTESIAN_POINT('',(-63.5,25.4,61.976));
#807=DIRECTION('',(0.,0.,-1.));
#808=DIRECTION('',(-1.,0.,0.));
#809=AXIS2_PLACEMENT_3D('',#806,#807,#808);
#810=PLANE('',#809);
#811=ORIENTED_EDGE('',*,*,#266,.F.);
#812=DIRECTION('',(0.,1.,0.));
#813=VECTOR('',#812,1.);
#814=CARTESIAN_POINT('',(-60.96,25.4,61.976));
#815=LINE('',#814,#813);
#816=EDGE_CURVE('E523',#491,#257,#815,.F.);
#817=ORIENTED_EDGE('',*,*,#816,.F.);
#818=ORIENTED_EDGE('',*,*,#492,.T.);
#819=DIRECTION('',(0.,1.,0.));
#820=VECTOR('',#819,1.);
#821=CARTESIAN_POINT('',(60.96,25.4,61.976));
#822=LINE('',#821,#820);
#823=EDGE_CURVE('E309',#265,#483,#822,.T.);
#824=ORIENTED_EDGE('',*,*,#823,.F.);
#825=EDGE_LOOP('',(#811,#817,#818,#824));
#826=FACE_BOUND('',#825,.T.);
#827=ADVANCED_FACE('F602',(#826),#810,.T.);
#828=CARTESIAN_POINT('',(61.976,1.524,-21.336));
#829=VERTEX_POINT('',#828);
#830=CARTESIAN_POINT('',(61.976,1.524,-60.96));
#831=VERTEX_POINT('',#830);
#832=EDGE_CURVE('E453',#829,#831,#67,.T.);
#833=ORIENTED_EDGE('',*,*,#832,.F.);
#834=DIRECTION('',(0.,-1.,0.));
#835=VECTOR('',#834,1.);
#836=CARTESIAN_POINT('',(61.976,25.4,-21.336));
#837=LINE('',#836,#835);
#838=EDGE_CURVE('E56',#829,#639,#837,.F.);
#839=ORIENTED_EDGE('',*,*,#838,.T.);
#840=ORIENTED_EDGE('',*,*,#640,.T.);
#841=DIRECTION('',(0.,1.,0.));
#842=VECTOR('',#841,1.);
#843=CARTESIAN_POINT('',(61.976,25.4,-60.96));
#844=LINE('',#843,#842);
#845=EDGE_CURVE('E457',#831,#635,#844,.T.);
#846=ORIENTED_EDGE('',*,*,#845,.F.);
#847=EDGE_LOOP('',(#833,#839,#840,#846));
#848=FACE_BOUND('',#847,.T.);
#849=ADVANCED_FACE('F455',(#848),#63,.T.);
#850=CARTESIAN_POINT('',(-63.5,25.4,-61.976));
#851=DIRECTION('',(0.,0.,1.));
#852=DIRECTION('',(1.,0.,0.));
#853=AXIS2_PLACEMENT_3D('',#850,#851,#852);
#854=PLANE('',#853);
#855=DIRECTION('',(-1.,0.,0.));
#856=VECTOR('',#855,1.);
#857=CARTESIAN_POINT('',(-63.5,1.524,-61.976));
#858=LINE('',#857,#856);
#859=CARTESIAN_POINT('',(60.96,1.524,-61.976));
#860=VERTEX_POINT('',#859);
#861=CARTESIAN_POINT('',(-60.96,1.524,-61.976));
#862=VERTEX_POINT('',#861);
#863=EDGE_CURVE('E265',#860,#862,#858,.T.);
#864=ORIENTED_EDGE('',*,*,#863,.F.);
#865=DIRECTION('',(0.,1.,0.));
#866=VECTOR('',#865,1.);
#867=CARTESIAN_POINT('',(60.96,25.4,-61.976));
#868=LINE('',#867,#866);
#869=EDGE_CURVE('E261',#626,#860,#868,.F.);
#870=ORIENTED_EDGE('',*,*,#869,.F.);
#871=ORIENTED_EDGE('',*,*,#627,.T.);
#872=DIRECTION('',(0.,1.,0.));
#873=VECTOR('',#872,1.);
#874=CARTESIAN_POINT('',(-60.96,25.4,-61.976));
#875=LINE('',#874,#873);
#876=EDGE_CURVE('E254',#862,#618,#875,.T.);
#877=ORIENTED_EDGE('',*,*,#876,.F.);
#878=EDGE_LOOP('',(#864,#870,#871,#877));
#879=FACE_BOUND('',#878,.T.);
#880=ADVANCED_FACE('F274',(#879),#854,.T.);
#881=CARTESIAN_POINT('',(-41.275,1.524,-41.275));
#882=DIRECTION('',(0.,1.,0.));
#883=DIRECTION('',(0.,0.,1.));
#884=AXIS2_PLACEMENT_3D('',#881,#882,#883);
#885=CIRCLE('',#884,3.175);
#886=CARTESIAN_POINT('',(-41.275,1.524,-38.1));
#887=VERTEX_POINT('',#886);
#888=EDGE_CURVE('E1053',#887,#887,#885,.T.);
#889=ORIENTED_EDGE('',*,*,#888,.F.);
#890=EDGE_LOOP('',(#889));
#891=FACE_BOUND('',#890,.T.);
#892=CARTESIAN_POINT('',(44.45,1.524,-41.275));
#893=DIRECTION('',(0.,1.,0.));
#894=DIRECTION('',(0.,0.,1.));
#895=AXIS2_PLACEMENT_3D('',#892,#893,#894);
#896=CIRCLE('',#895,3.175);
#897=CARTESIAN_POINT('',(44.45,1.524,-38.1));
#898=VERTEX_POINT('',#897);
#899=EDGE_CURVE('E504',#898,#898,#896,.T.);
#900=ORIENTED_EDGE('',*,*,#899,.F.);
#901=EDGE_LOOP('',(#900));
#902=FACE_BOUND('',#901,.T.);
#903=ORIENTED_EDGE('',*,*,#795,.T.);
#904=CARTESIAN_POINT('',(-60.96,1.524,-21.336));
#905=DIRECTION('',(0.,1.,0.));
#906=DIRECTION('',(0.,0.,1.));
#907=AXIS2_PLACEMENT_3D('',#904,#905,#906);
#908=CIRCLE('',#907,1.016);
#909=CARTESIAN_POINT('',(-60.96,1.524,-20.32));
#910=VERTEX_POINT('',#909);
#911=EDGE_CURVE('E374',#790,#910,#908,.T.);
#912=ORIENTED_EDGE('',*,*,#911,.T.);
#913=DIRECTION('',(-1.,0.,0.));
#914=VECTOR('',#913,1.);
#915=CARTESIAN_POINT('',(-63.5,1.524,-20.32));
#916=LINE('',#915,#914);
#917=CARTESIAN_POINT('',(60.96,1.524,-20.32));
#918=VERTEX_POINT('',#917);
#919=EDGE_CURVE('E363',#918,#910,#916,.T.);
#920=ORIENTED_EDGE('',*,*,#919,.F.);
#921=CARTESIAN_POINT('',(60.96,1.524,-21.336));
#922=DIRECTION('',(0.,1.,0.));
#923=DIRECTION('',(0.,0.,1.));
#924=AXIS2_PLACEMENT_3D('',#921,#922,#923);
#925=CIRCLE('',#924,1.016);
#926=EDGE_CURVE('E372',#918,#829,#925,.T.);
#927=ORIENTED_EDGE('',*,*,#926,.T.);
#928=ORIENTED_EDGE('',*,*,#832,.T.);
#929=CARTESIAN_POINT('',(60.96,1.524,-60.96));
#930=DIRECTION('',(0.,1.,0.));
#931=DIRECTION('',(0.,0.,1.));
#932=AXIS2_PLACEMENT_3D('',#929,#930,#931);
#933=CIRCLE('',#932,1.016);
#934=EDGE_CURVE('E262',#860,#831,#933,.F.);
#935=ORIENTED_EDGE('',*,*,#934,.F.);
#936=ORIENTED_EDGE('',*,*,#863,.T.);
#937=CARTESIAN_POINT('',(-60.96,1.524,-60.96));
#938=DIRECTION('',(0.,1.,0.));
#939=DIRECTION('',(0.,0.,1.));
#940=AXIS2_PLACEMENT_3D('',#937,#938,#939);
#941=CIRCLE('',#940,1.016);
#942=EDGE_CURVE('E250',#794,#862,#941,.F.);
#943=ORIENTED_EDGE('',*,*,#942,.F.);
#944=EDGE_LOOP('',(#903,#912,#920,#927,#928,#935,#936,#943));
#945=FACE_BOUND('',#944,.T.);
#946=ADVANCED_FACE('F266',(#891,#902,#945),#103,.T.);
#947=CARTESIAN_POINT('',(-60.96,25.4,-60.96));
#948=DIRECTION('',(0.,-1.,0.));
#949=DIRECTION('',(0.,0.,-1.));
#950=AXIS2_PLACEMENT_3D('',#947,#948,#949);
#951=CYLINDRICAL_SURFACE('',#950,1.016);
#952=ORIENTED_EDGE('',*,*,#619,.T.);
#953=ORIENTED_EDGE('',*,*,#801,.T.);
#954=ORIENTED_EDGE('',*,*,#942,.T.);
#955=ORIENTED_EDGE('',*,*,#876,.T.);
#956=EDGE_LOOP('',(#952,#953,#954,#955));
#957=FACE_BOUND('',#956,.T.);
#958=ADVANCED_FACE('F252',(#957),#951,.F.);
#959=CARTESIAN_POINT('',(60.96,25.4,-60.96));
#960=DIRECTION('',(0.,-1.,0.));
#961=DIRECTION('',(0.,0.,-1.));
#962=AXIS2_PLACEMENT_3D('',#959,#960,#961);
#963=CYLINDRICAL_SURFACE('',#962,1.016);
#964=ORIENTED_EDGE('',*,*,#636,.T.);
#965=ORIENTED_EDGE('',*,*,#869,.T.);
#966=ORIENTED_EDGE('',*,*,#934,.T.);
#967=ORIENTED_EDGE('',*,*,#845,.T.);
#968=EDGE_LOOP('',(#964,#965,#966,#967));
#969=FACE_BOUND('',#968,.T.);
#970=ADVANCED_FACE('F527',(#969),#963,.F.);
#971=CARTESIAN_POINT('',(60.96,25.4,60.96));
#972=DIRECTION('',(0.,-1.,0.));
#973=DIRECTION('',(0.,0.,-1.));
#974=AXIS2_PLACEMENT_3D('',#971,#972,#973);
#975=CYLINDRICAL_SURFACE('',#974,1.016);
#976=ORIENTED_EDGE('',*,*,#484,.T.);
#977=ORIENTED_EDGE('',*,*,#206,.T.);
#978=ORIENTED_EDGE('',*,*,#273,.T.);
#979=ORIENTED_EDGE('',*,*,#823,.T.);
#980=EDGE_LOOP('',(#976,#977,#978,#979));
#981=FACE_BOUND('',#980,.T.);
#982=ADVANCED_FACE('F805',(#981),#975,.F.);
#983=CARTESIAN_POINT('',(-60.96,25.4,60.96));
#984=DIRECTION('',(0.,-1.,0.));
#985=DIRECTION('',(0.,0.,-1.));
#986=AXIS2_PLACEMENT_3D('',#983,#984,#985);
#987=CYLINDRICAL_SURFACE('',#986,1.016);
#988=ORIENTED_EDGE('',*,*,#499,.T.);
#989=ORIENTED_EDGE('',*,*,#816,.T.);
#990=ORIENTED_EDGE('',*,*,#258,.T.);
#991=ORIENTED_EDGE('',*,*,#179,.T.);
#992=EDGE_LOOP('',(#988,#989,#990,#991));
#993=FACE_BOUND('',#992,.T.);
#994=ADVANCED_FACE('F674',(#993),#987,.F.);
#995=CARTESIAN_POINT('',(-61.976,25.4,-20.32));
#996=DIRECTION('',(0.,0.,-1.));
#997=DIRECTION('',(-1.,0.,0.));
#998=AXIS2_PLACEMENT_3D('',#995,#996,#997);
#999=PLANE('',#998);
#1000=ORIENTED_EDGE('',*,*,#919,.T.);
#1001=DIRECTION('',(0.,-1.,0.));
#1002=VECTOR('',#1001,1.);
#1003=CARTESIAN_POINT('',(-60.96,25.4,-20.32));
#1004=LINE('',#1003,#1002);
#1005=EDGE_CURVE('E379',#910,#594,#1004,.F.);
#1006=ORIENTED_EDGE('',*,*,#1005,.T.);
#1007=ORIENTED_EDGE('',*,*,#597,.T.);
#1008=DIRECTION('',(0.,-1.,0.));
#1009=VECTOR('',#1008,1.);
#1010=CARTESIAN_POINT('',(60.96,1.524,-20.32));
#1011=LINE('',#1010,#1009);
#1012=EDGE_CURVE('E376',#596,#918,#1011,.T.);
#1013=ORIENTED_EDGE('',*,*,#1012,.T.);
#1014=EDGE_LOOP('',(#1000,#1006,#1007,#1013));
#1015=FACE_BOUND('',#1014,.T.);
#1016=ADVANCED_FACE('F446',(#1015),#999,.T.);
#1017=CARTESIAN_POINT('',(-61.976,25.4,-17.78));
#1018=DIRECTION('',(0.,0.,-1.));
#1019=DIRECTION('',(-1.,0.,0.));
#1020=AXIS2_PLACEMENT_3D('',#1017,#1018,#1019);
#1021=PLANE('',#1020);
#1022=ORIENTED_EDGE('',*,*,#544,.F.);
#1023=DIRECTION('',(0.,-1.,0.));
#1024=VECTOR('',#1023,1.);
#1025=CARTESIAN_POINT('',(-60.96,25.4,-17.78));
#1026=LINE('',#1025,#1024);
#1027=EDGE_CURVE('E383',#535,#111,#1026,.T.);
#1028=ORIENTED_EDGE('',*,*,#1027,.T.);
#1029=ORIENTED_EDGE('',*,*,#112,.F.);
#1030=DIRECTION('',(0.,-1.,0.));
#1031=VECTOR('',#1030,1.);
#1032=CARTESIAN_POINT('',(60.96,25.4,-17.78));
#1033=LINE('',#1032,#1031);
#1034=EDGE_CURVE('E381',#109,#543,#1033,.F.);
#1035=ORIENTED_EDGE('',*,*,#1034,.T.);
#1036=EDGE_LOOP('',(#1022,#1028,#1029,#1035));
#1037=FACE_BOUND('',#1036,.T.);
#1038=ADVANCED_FACE('F779',(#1037),#1021,.F.);
#1039=CARTESIAN_POINT('',(61.976,25.4,20.32));
#1040=DIRECTION('',(0.,0.,1.));
#1041=DIRECTION('',(1.,0.,0.));
#1042=AXIS2_PLACEMENT_3D('',#1039,#1040,#1041);
#1043=PLANE('',#1042);
#1044=ORIENTED_EDGE('',*,*,#467,.T.);
#1045=DIRECTION('',(0.,-1.,0.));
#1046=VECTOR('',#1045,1.);
#1047=CARTESIAN_POINT('',(-60.96,1.524,20.32));
#1048=LINE('',#1047,#1046);
#1049=EDGE_CURVE('E406',#458,#238,#1048,.T.);
#1050=ORIENTED_EDGE('',*,*,#1049,.T.);
#1051=ORIENTED_EDGE('',*,*,#241,.T.);
#1052=DIRECTION('',(0.,-1.,0.));
#1053=VECTOR('',#1052,1.);
#1054=CARTESIAN_POINT('',(60.96,25.4,20.32));
#1055=LINE('',#1054,#1053);
#1056=EDGE_CURVE('E404',#240,#466,#1055,.F.);
#1057=ORIENTED_EDGE('',*,*,#1056,.T.);
#1058=EDGE_LOOP('',(#1044,#1050,#1051,#1057));
#1059=FACE_BOUND('',#1058,.T.);
#1060=ADVANCED_FACE('F488',(#1059),#1043,.T.);
#1061=CARTESIAN_POINT('',(61.976,25.4,17.78));
#1062=DIRECTION('',(0.,0.,1.));
#1063=DIRECTION('',(1.,0.,0.));
#1064=AXIS2_PLACEMENT_3D('',#1061,#1062,#1063);
#1065=PLANE('',#1064);
#1066=ORIENTED_EDGE('',*,*,#137,.F.);
#1067=DIRECTION('',(0.,-1.,0.));
#1068=VECTOR('',#1067,1.);
#1069=CARTESIAN_POINT('',(-60.96,25.4,17.78));
#1070=LINE('',#1069,#1068);
#1071=EDGE_CURVE('E402',#128,#518,#1070,.F.);
#1072=ORIENTED_EDGE('',*,*,#1071,.T.);
#1073=ORIENTED_EDGE('',*,*,#519,.F.);
#1074=DIRECTION('',(0.,-1.,0.));
#1075=VECTOR('',#1074,1.);
#1076=CARTESIAN_POINT('',(60.96,25.4,17.78));
#1077=LINE('',#1076,#1075);
#1078=EDGE_CURVE('E399',#510,#136,#1077,.T.);
#1079=ORIENTED_EDGE('',*,*,#1078,.T.);
#1080=EDGE_LOOP('',(#1066,#1072,#1073,#1079));
#1081=FACE_BOUND('',#1080,.T.);
#1082=ADVANCED_FACE('F616',(#1081),#1065,.F.);
#1083=CARTESIAN_POINT('',(-60.96,25.4,-21.336));
#1084=DIRECTION('',(0.,1.,0.));
#1085=DIRECTION('',(0.,0.,1.));
#1086=AXIS2_PLACEMENT_3D('',#1083,#1084,#1085);
#1087=CYLINDRICAL_SURFACE('',#1086,1.016);
#1088=ORIENTED_EDGE('',*,*,#606,.F.);
#1089=ORIENTED_EDGE('',*,*,#1005,.F.);
#1090=ORIENTED_EDGE('',*,*,#911,.F.);
#1091=ORIENTED_EDGE('',*,*,#791,.F.);
#1092=EDGE_LOOP('',(#1088,#1089,#1090,#1091));
#1093=FACE_BOUND('',#1092,.T.);
#1094=ADVANCED_FACE('F613',(#1093),#1087,.F.);
#1095=CARTESIAN_POINT('',(-60.96,25.4,-16.764));
#1096=DIRECTION('',(0.,-1.,0.));
#1097=DIRECTION('',(0.,0.,-1.));
#1098=AXIS2_PLACEMENT_3D('',#1095,#1096,#1097);
#1099=CYLINDRICAL_SURFACE('',#1098,1.016);
#1100=ORIENTED_EDGE('',*,*,#536,.F.);
#1101=ORIENTED_EDGE('',*,*,#40,.F.);
#1102=ORIENTED_EDGE('',*,*,#119,.F.);
#1103=ORIENTED_EDGE('',*,*,#1027,.F.);
#1104=EDGE_LOOP('',(#1100,#1101,#1102,#1103));
#1105=FACE_BOUND('',#1104,.T.);
#1106=ADVANCED_FACE('F615',(#1105),#1099,.F.);
#1107=CARTESIAN_POINT('',(-60.96,25.4,16.764));
#1108=DIRECTION('',(0.,-1.,0.));
#1109=DIRECTION('',(0.,0.,-1.));
#1110=AXIS2_PLACEMENT_3D('',#1107,#1108,#1109);
#1111=CYLINDRICAL_SURFACE('',#1110,1.016);
#1112=ORIENTED_EDGE('',*,*,#526,.F.);
#1113=ORIENTED_EDGE('',*,*,#1071,.F.);
#1114=ORIENTED_EDGE('',*,*,#129,.F.);
#1115=ORIENTED_EDGE('',*,*,#54,.F.);
#1116=EDGE_LOOP('',(#1112,#1113,#1114,#1115));
#1117=FACE_BOUND('',#1116,.T.);
#1118=ADVANCED_FACE('F622',(#1117),#1111,.F.);
#1119=CARTESIAN_POINT('',(-60.96,25.4,21.336));
#1120=DIRECTION('',(0.,1.,0.));
#1121=DIRECTION('',(0.,0.,1.));
#1122=AXIS2_PLACEMENT_3D('',#1119,#1120,#1121);
#1123=CYLINDRICAL_SURFACE('',#1122,1.016);
#1124=ORIENTED_EDGE('',*,*,#459,.F.);
#1125=ORIENTED_EDGE('',*,*,#169,.F.);
#1126=ORIENTED_EDGE('',*,*,#248,.F.);
#1127=ORIENTED_EDGE('',*,*,#1049,.F.);
#1128=EDGE_LOOP('',(#1124,#1125,#1126,#1127));
#1129=FACE_BOUND('',#1128,.T.);
#1130=ADVANCED_FACE('F631',(#1129),#1123,.F.);
#1131=CARTESIAN_POINT('',(60.96,25.4,21.336));
#1132=DIRECTION('',(0.,1.,0.));
#1133=DIRECTION('',(0.,0.,1.));
#1134=AXIS2_PLACEMENT_3D('',#1131,#1132,#1133);
#1135=CYLINDRICAL_SURFACE('',#1134,1.016);
#1136=ORIENTED_EDGE('',*,*,#474,.F.);
#1137=ORIENTED_EDGE('',*,*,#1056,.F.);
#1138=ORIENTED_EDGE('',*,*,#281,.F.);
#1139=ORIENTED_EDGE('',*,*,#196,.F.);
#1140=EDGE_LOOP('',(#1136,#1137,#1138,#1139));
#1141=FACE_BOUND('',#1140,.T.);
#1142=ADVANCED_FACE('F483',(#1141),#1135,.F.);
#1143=CARTESIAN_POINT('',(60.96,25.4,16.764));
#1144=DIRECTION('',(0.,-1.,0.));
#1145=DIRECTION('',(0.,0.,-1.));
#1146=AXIS2_PLACEMENT_3D('',#1143,#1144,#1145);
#1147=CYLINDRICAL_SURFACE('',#1146,1.016);
#1148=ORIENTED_EDGE('',*,*,#511,.F.);
#1149=ORIENTED_EDGE('',*,*,#80,.F.);
#1150=ORIENTED_EDGE('',*,*,#144,.F.);
#1151=ORIENTED_EDGE('',*,*,#1078,.F.);
#1152=EDGE_LOOP('',(#1148,#1149,#1150,#1151));
#1153=FACE_BOUND('',#1152,.T.);
#1154=ADVANCED_FACE('F638',(#1153),#1147,.F.);
#1155=CARTESIAN_POINT('',(60.96,25.4,-21.336));
#1156=DIRECTION('',(0.,1.,0.));
#1157=DIRECTION('',(0.,0.,1.));
#1158=AXIS2_PLACEMENT_3D('',#1155,#1156,#1157);
#1159=CYLINDRICAL_SURFACE('',#1158,1.016);
#1160=ORIENTED_EDGE('',*,*,#647,.F.);
#1161=ORIENTED_EDGE('',*,*,#838,.F.);
#1162=ORIENTED_EDGE('',*,*,#926,.F.);
#1163=ORIENTED_EDGE('',*,*,#1012,.F.);
#1164=EDGE_LOOP('',(#1160,#1161,#1162,#1163));
#1165=FACE_BOUND('',#1164,.T.);
#1166=ADVANCED_FACE('F452',(#1165),#1159,.F.);
#1167=CARTESIAN_POINT('',(60.96,25.4,-16.764));
#1168=DIRECTION('',(0.,-1.,0.));
#1169=DIRECTION('',(0.,0.,-1.));
#1170=AXIS2_PLACEMENT_3D('',#1167,#1168,#1169);
#1171=CYLINDRICAL_SURFACE('',#1170,1.016);
#1172=ORIENTED_EDGE('',*,*,#551,.F.);
#1173=ORIENTED_EDGE('',*,*,#1034,.F.);
#1174=ORIENTED_EDGE('',*,*,#152,.F.);
#1175=ORIENTED_EDGE('',*,*,#94,.F.);
#1176=EDGE_LOOP('',(#1172,#1173,#1174,#1175));
#1177=FACE_BOUND('',#1176,.T.);
#1178=ADVANCED_FACE('F43',(#1177),#1171,.F.);
#1179=CARTESIAN_POINT('',(44.45,0.,-41.275));
#1180=DIRECTION('',(0.,1.,0.));
#1181=DIRECTION('',(0.,0.,1.));
#1182=AXIS2_PLACEMENT_3D('',#1179,#1180,#1181);
#1183=CYLINDRICAL_SURFACE('',#1182,3.175);
#1184=ORIENTED_EDGE('',*,*,#697,.F.);
#1185=EDGE_LOOP('',(#1184));
#1186=FACE_BOUND('',#1185,.T.);
#1187=ORIENTED_EDGE('',*,*,#899,.T.);
#1188=EDGE_LOOP('',(#1187));
#1189=FACE_BOUND('',#1188,.T.);
#1190=ADVANCED_FACE('F645',(#1186,#1189),#1183,.F.);
#1191=CARTESIAN_POINT('',(-41.275,0.,-41.275));
#1192=DIRECTION('',(0.,1.,0.));
#1193=DIRECTION('',(0.,0.,1.));
#1194=AXIS2_PLACEMENT_3D('',#1191,#1192,#1193);
#1195=CYLINDRICAL_SURFACE('',#1194,3.175);
#1196=ORIENTED_EDGE('',*,*,#686,.F.);
#1197=EDGE_LOOP('',(#1196));
#1198=FACE_BOUND('',#1197,.T.);
#1199=ORIENTED_EDGE('',*,*,#888,.T.);
#1200=EDGE_LOOP('',(#1199));
#1201=FACE_BOUND('',#1200,.T.);
#1202=ADVANCED_FACE('F650',(#1198,#1201),#1195,.F.);
#1203=CARTESIAN_POINT('',(44.45,0.,41.275));
#1204=DIRECTION('',(0.,1.,0.));
#1205=DIRECTION('',(0.,0.,1.));
#1206=AXIS2_PLACEMENT_3D('',#1203,#1204,#1205);
#1207=CYLINDRICAL_SURFACE('',#1206,3.175);
#1208=ORIENTED_EDGE('',*,*,#675,.F.);
#1209=EDGE_LOOP('',(#1208));
#1210=FACE_BOUND('',#1209,.T.);
#1211=ORIENTED_EDGE('',*,*,#229,.T.);
#1212=EDGE_LOOP('',(#1211));
#1213=FACE_BOUND('',#1212,.T.);
#1214=ADVANCED_FACE('F696',(#1210,#1213),#1207,.F.);
#1215=CARTESIAN_POINT('',(-41.275,0.,41.275));
#1216=DIRECTION('',(0.,1.,0.));
#1217=DIRECTION('',(0.,0.,1.));
#1218=AXIS2_PLACEMENT_3D('',#1215,#1216,#1217);
#1219=CYLINDRICAL_SURFACE('',#1218,3.175);
#1220=ORIENTED_EDGE('',*,*,#664,.F.);
#1221=EDGE_LOOP('',(#1220));
#1222=FACE_BOUND('',#1221,.T.);
#1223=ORIENTED_EDGE('',*,*,#218,.T.);
#1224=EDGE_LOOP('',(#1223));
#1225=FACE_BOUND('',#1224,.T.);
#1226=ADVANCED_FACE('F690',(#1222,#1225),#1219,.F.);
#1227=CLOSED_SHELL('',(#58,#98,#156,#183,#210,#285,#325,#365,#405,#445,#651,#735,#747,#759,#771,
#783,#805,#827,#849,#880,#946,#958,#970,#982,#994,#1016,#1038,#1060,#1082,#1094,#1106,#1118,
#1130,#1142,#1154,#1166,#1178,#1190,#1202,#1214,#1226));
#1228=MANIFOLD_SOLID_BREP('B2',#1227);
#1229=ADVANCED_BREP_SHAPE_REPRESENTATION('',(#18,#1228),#14);
#1230=SHAPE_DEFINITION_REPRESENTATION(#9,#1229);
ENDSEC;
END-ISO-10303-21;
